VERSION 5.7 ;
  NOWIREEXTENSIONATPIN ON ;
  DIVIDERCHAR "/" ;
  BUSBITCHARS "[]" ;
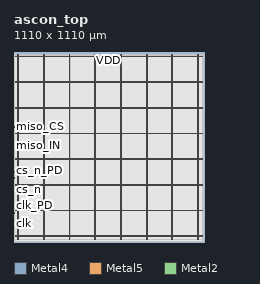
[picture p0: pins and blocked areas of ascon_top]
MACRO ascon_top
  CLASS BLOCK ;
  FOREIGN ascon_top ;
  ORIGIN 0.000 0.000 ;
  SIZE 1110.000 BY 1110.000 ;
  PIN VDD
    DIRECTION INOUT ;
    USE POWER ;
    PORT
      LAYER Metal4 ;
        RECT 22.240 15.380 23.840 1093.980 ;
    END
    PORT
      LAYER Metal4 ;
        RECT 172.240 15.380 173.840 1093.980 ;
    END
    PORT
      LAYER Metal4 ;
        RECT 322.240 15.380 323.840 1093.980 ;
    END
    PORT
      LAYER Metal4 ;
        RECT 472.240 15.380 473.840 1093.980 ;
    END
    PORT
      LAYER Metal4 ;
        RECT 622.240 15.380 623.840 1093.980 ;
    END
    PORT
      LAYER Metal4 ;
        RECT 772.240 15.380 773.840 1093.980 ;
    END
    PORT
      LAYER Metal4 ;
        RECT 922.240 15.380 923.840 1093.980 ;
    END
    PORT
      LAYER Metal4 ;
        RECT 1072.240 15.380 1073.840 1093.980 ;
    END
    PORT
      LAYER Metal5 ;
        RECT 6.720 31.530 1103.200 33.130 ;
    END
    PORT
      LAYER Metal5 ;
        RECT 6.720 181.530 1103.200 183.130 ;
    END
    PORT
      LAYER Metal5 ;
        RECT 6.720 331.530 1103.200 333.130 ;
    END
    PORT
      LAYER Metal5 ;
        RECT 6.720 481.530 1103.200 483.130 ;
    END
    PORT
      LAYER Metal5 ;
        RECT 6.720 631.530 1103.200 633.130 ;
    END
    PORT
      LAYER Metal5 ;
        RECT 6.720 781.530 1103.200 783.130 ;
    END
    PORT
      LAYER Metal5 ;
        RECT 6.720 931.530 1103.200 933.130 ;
    END
    PORT
      LAYER Metal5 ;
        RECT 6.720 1081.530 1103.200 1083.130 ;
    END
  END VDD
  PIN VSS
    DIRECTION INOUT ;
    USE GROUND ;
    PORT
      LAYER Metal4 ;
        RECT 25.540 15.380 27.140 1093.980 ;
    END
    PORT
      LAYER Metal4 ;
        RECT 175.540 15.380 177.140 1093.980 ;
    END
    PORT
      LAYER Metal4 ;
        RECT 325.540 15.380 327.140 1093.980 ;
    END
    PORT
      LAYER Metal4 ;
        RECT 475.540 15.380 477.140 1093.980 ;
    END
    PORT
      LAYER Metal4 ;
        RECT 625.540 15.380 627.140 1093.980 ;
    END
    PORT
      LAYER Metal4 ;
        RECT 775.540 15.380 777.140 1093.980 ;
    END
    PORT
      LAYER Metal4 ;
        RECT 925.540 15.380 927.140 1093.980 ;
    END
    PORT
      LAYER Metal4 ;
        RECT 1075.540 15.380 1077.140 1093.980 ;
    END
    PORT
      LAYER Metal5 ;
        RECT 6.720 34.830 1103.200 36.430 ;
    END
    PORT
      LAYER Metal5 ;
        RECT 6.720 184.830 1103.200 186.430 ;
    END
    PORT
      LAYER Metal5 ;
        RECT 6.720 334.830 1103.200 336.430 ;
    END
    PORT
      LAYER Metal5 ;
        RECT 6.720 484.830 1103.200 486.430 ;
    END
    PORT
      LAYER Metal5 ;
        RECT 6.720 634.830 1103.200 636.430 ;
    END
    PORT
      LAYER Metal5 ;
        RECT 6.720 784.830 1103.200 786.430 ;
    END
    PORT
      LAYER Metal5 ;
        RECT 6.720 934.830 1103.200 936.430 ;
    END
    PORT
      LAYER Metal5 ;
        RECT 6.720 1084.830 1103.200 1086.430 ;
    END
  END VSS
  PIN clk
    DIRECTION INPUT ;
    USE SIGNAL ;
    ANTENNAGATEAREA 4.738000 ;
    ANTENNADIFFAREA 0.410400 ;
    PORT
      LAYER Metal2 ;
        RECT 0.000 108.760 1.000 109.140 ;
    END
  END clk
  PIN clk_PD
    DIRECTION OUTPUT ;
    USE SIGNAL ;
    ANTENNADIFFAREA 0.360800 ;
    PORT
      LAYER Metal2 ;
        RECT 0.000 169.290 1.000 169.670 ;
    END
  END clk_PD
  PIN clk_PU
    DIRECTION OUTPUT ;
    USE SIGNAL ;
    ANTENNADIFFAREA 0.360800 ;
    PORT
      LAYER Metal2 ;
        RECT 0.000 173.655 1.000 174.035 ;
    END
  END clk_PU
  PIN cs_n
    DIRECTION INPUT ;
    USE SIGNAL ;
    ANTENNAGATEAREA 0.396000 ;
    ANTENNADIFFAREA 0.410400 ;
    PORT
      LAYER Metal2 ;
        RECT 0.000 308.760 1.000 309.140 ;
    END
  END cs_n
  PIN cs_n_PD
    DIRECTION OUTPUT ;
    USE SIGNAL ;
    ANTENNADIFFAREA 0.360800 ;
    PORT
      LAYER Metal2 ;
        RECT 0.000 369.290 1.000 369.670 ;
    END
  END cs_n_PD
  PIN cs_n_PU
    DIRECTION OUTPUT ;
    USE SIGNAL ;
    ANTENNADIFFAREA 0.360800 ;
    PORT
      LAYER Metal2 ;
        RECT 0.000 373.655 1.000 374.035 ;
    END
  END cs_n_PU
  PIN miso_CS
    DIRECTION OUTPUT ;
    USE SIGNAL ;
    ANTENNADIFFAREA 0.360800 ;
    PORT
      LAYER Metal2 ;
        RECT 0.000 676.260 1.000 676.640 ;
    END
  END miso_CS
  PIN miso_IE
    DIRECTION OUTPUT ;
    USE SIGNAL ;
    ANTENNADIFFAREA 0.360800 ;
    PORT
      LAYER Metal2 ;
        RECT 0.000 668.235 1.000 668.615 ;
    END
  END miso_IE
  PIN miso_IN
    DIRECTION INPUT ;
    USE SIGNAL ;
    ANTENNAGATEAREA 0.498500 ;
    ANTENNADIFFAREA 0.410400 ;
    PORT
      LAYER Metal2 ;
        RECT 0.000 608.760 1.000 609.140 ;
    END
  END miso_IN
  PIN miso_OE
    DIRECTION OUTPUT ;
    USE SIGNAL ;
    ANTENNADIFFAREA 0.536800 ;
    PORT
      LAYER Metal2 ;
        RECT 0.000 609.490 1.000 609.870 ;
    END
  END miso_OE
  PIN miso_OUT
    DIRECTION OUTPUT ;
    USE SIGNAL ;
    ANTENNADIFFAREA 2.080400 ;
    PORT
      LAYER Metal2 ;
        RECT 0.000 610.220 1.000 610.600 ;
    END
  END miso_OUT
  PIN miso_PD
    DIRECTION OUTPUT ;
    USE SIGNAL ;
    ANTENNADIFFAREA 0.360800 ;
    PORT
      LAYER Metal2 ;
        RECT 0.000 669.290 1.000 669.670 ;
    END
  END miso_PD
  PIN miso_PDRV0
    DIRECTION OUTPUT ;
    USE SIGNAL ;
    ANTENNADIFFAREA 0.536800 ;
    PORT
      LAYER Metal2 ;
        RECT 0.000 672.510 1.000 672.890 ;
    END
  END miso_PDRV0
  PIN miso_PDRV1
    DIRECTION OUTPUT ;
    USE SIGNAL ;
    ANTENNADIFFAREA 0.360800 ;
    PORT
      LAYER Metal2 ;
        RECT 0.000 671.800 1.000 672.180 ;
    END
  END miso_PDRV1
  PIN miso_PU
    DIRECTION OUTPUT ;
    USE SIGNAL ;
    ANTENNADIFFAREA 0.360800 ;
    PORT
      LAYER Metal2 ;
        RECT 0.000 673.655 1.000 674.035 ;
    END
  END miso_PU
  PIN miso_SL
    DIRECTION OUTPUT ;
    USE SIGNAL ;
    ANTENNADIFFAREA 0.360800 ;
    PORT
      LAYER Metal2 ;
        RECT 0.000 610.950 1.000 611.330 ;
    END
  END miso_SL
  PIN mosi
    DIRECTION INPUT ;
    USE SIGNAL ;
    ANTENNAGATEAREA 0.396000 ;
    ANTENNADIFFAREA 0.410400 ;
    PORT
      LAYER Metal2 ;
        RECT 0.000 508.760 1.000 509.140 ;
    END
  END mosi
  PIN mosi_PD
    DIRECTION OUTPUT ;
    USE SIGNAL ;
    ANTENNADIFFAREA 0.360800 ;
    PORT
      LAYER Metal2 ;
        RECT 0.000 569.290 1.000 569.670 ;
    END
  END mosi_PD
  PIN mosi_PU
    DIRECTION OUTPUT ;
    USE SIGNAL ;
    ANTENNADIFFAREA 0.360800 ;
    PORT
      LAYER Metal2 ;
        RECT 0.000 573.655 1.000 574.035 ;
    END
  END mosi_PU
  PIN rst
    DIRECTION INPUT ;
    USE SIGNAL ;
    ANTENNAGATEAREA 1.452000 ;
    ANTENNADIFFAREA 0.820800 ;
    PORT
      LAYER Metal2 ;
        RECT 0.000 208.760 1.000 209.140 ;
    END
  END rst
  PIN rst_PD
    DIRECTION OUTPUT ;
    USE SIGNAL ;
    ANTENNADIFFAREA 0.360800 ;
    PORT
      LAYER Metal2 ;
        RECT 0.000 269.290 1.000 269.670 ;
    END
  END rst_PD
  PIN rst_PU
    DIRECTION OUTPUT ;
    USE SIGNAL ;
    ANTENNADIFFAREA 0.360800 ;
    PORT
      LAYER Metal2 ;
        RECT 0.000 273.655 1.000 274.035 ;
    END
  END rst_PU
  PIN sclk
    DIRECTION INPUT ;
    USE SIGNAL ;
    ANTENNAGATEAREA 0.396000 ;
    ANTENNADIFFAREA 0.410400 ;
    PORT
      LAYER Metal2 ;
        RECT 0.000 408.760 1.000 409.140 ;
    END
  END sclk
  PIN sclk_PD
    DIRECTION OUTPUT ;
    USE SIGNAL ;
    ANTENNADIFFAREA 0.360800 ;
    PORT
      LAYER Metal2 ;
        RECT 0.000 469.290 1.000 469.670 ;
    END
  END sclk_PD
  PIN sclk_PU
    DIRECTION OUTPUT ;
    USE SIGNAL ;
    ANTENNADIFFAREA 0.360800 ;
    PORT
      LAYER Metal2 ;
        RECT 0.000 473.655 1.000 474.035 ;
    END
  END sclk_PU
  OBS
      LAYER Nwell ;
        RECT 6.290 15.250 1103.630 1094.110 ;
      LAYER Metal1 ;
        RECT 6.720 15.380 1103.200 1093.980 ;
      LAYER Metal2 ;
        RECT 0.140 676.940 1104.180 1093.870 ;
        RECT 1.300 675.960 1104.180 676.940 ;
        RECT 0.140 674.335 1104.180 675.960 ;
        RECT 1.300 673.355 1104.180 674.335 ;
        RECT 0.140 673.190 1104.180 673.355 ;
        RECT 1.300 671.500 1104.180 673.190 ;
        RECT 0.140 669.970 1104.180 671.500 ;
        RECT 1.300 668.990 1104.180 669.970 ;
        RECT 0.140 668.915 1104.180 668.990 ;
        RECT 1.300 667.935 1104.180 668.915 ;
        RECT 0.140 611.630 1104.180 667.935 ;
        RECT 1.300 608.460 1104.180 611.630 ;
        RECT 0.140 574.335 1104.180 608.460 ;
        RECT 1.300 573.355 1104.180 574.335 ;
        RECT 0.140 569.970 1104.180 573.355 ;
        RECT 1.300 568.990 1104.180 569.970 ;
        RECT 0.140 509.440 1104.180 568.990 ;
        RECT 1.300 508.460 1104.180 509.440 ;
        RECT 0.140 474.335 1104.180 508.460 ;
        RECT 1.300 473.355 1104.180 474.335 ;
        RECT 0.140 469.970 1104.180 473.355 ;
        RECT 1.300 468.990 1104.180 469.970 ;
        RECT 0.140 409.440 1104.180 468.990 ;
        RECT 1.300 408.460 1104.180 409.440 ;
        RECT 0.140 374.335 1104.180 408.460 ;
        RECT 1.300 373.355 1104.180 374.335 ;
        RECT 0.140 369.970 1104.180 373.355 ;
        RECT 1.300 368.990 1104.180 369.970 ;
        RECT 0.140 309.440 1104.180 368.990 ;
        RECT 1.300 308.460 1104.180 309.440 ;
        RECT 0.140 274.335 1104.180 308.460 ;
        RECT 1.300 273.355 1104.180 274.335 ;
        RECT 0.140 269.970 1104.180 273.355 ;
        RECT 1.300 268.990 1104.180 269.970 ;
        RECT 0.140 209.440 1104.180 268.990 ;
        RECT 1.300 208.460 1104.180 209.440 ;
        RECT 0.140 174.335 1104.180 208.460 ;
        RECT 1.300 173.355 1104.180 174.335 ;
        RECT 0.140 169.970 1104.180 173.355 ;
        RECT 1.300 168.990 1104.180 169.970 ;
        RECT 0.140 109.440 1104.180 168.990 ;
        RECT 1.300 108.460 1104.180 109.440 ;
        RECT 0.140 2.890 1104.180 108.460 ;
      LAYER Metal3 ;
        RECT 0.090 2.940 1104.230 1093.820 ;
      LAYER Metal4 ;
        RECT 0.140 15.080 21.940 1090.230 ;
        RECT 24.140 15.080 25.240 1090.230 ;
        RECT 27.440 15.080 171.940 1090.230 ;
        RECT 174.140 15.080 175.240 1090.230 ;
        RECT 177.440 15.080 321.940 1090.230 ;
        RECT 324.140 15.080 325.240 1090.230 ;
        RECT 327.440 15.080 471.940 1090.230 ;
        RECT 474.140 15.080 475.240 1090.230 ;
        RECT 477.440 15.080 621.940 1090.230 ;
        RECT 624.140 15.080 625.240 1090.230 ;
        RECT 627.440 15.080 771.940 1090.230 ;
        RECT 774.140 15.080 775.240 1090.230 ;
        RECT 777.440 15.080 921.940 1090.230 ;
        RECT 924.140 15.080 925.240 1090.230 ;
        RECT 927.440 15.080 1071.940 1090.230 ;
        RECT 1074.140 15.080 1075.240 1090.230 ;
        RECT 1077.440 15.080 1100.820 1090.230 ;
        RECT 0.140 2.890 1100.820 15.080 ;
  END
END ascon_top
END LIBRARY

